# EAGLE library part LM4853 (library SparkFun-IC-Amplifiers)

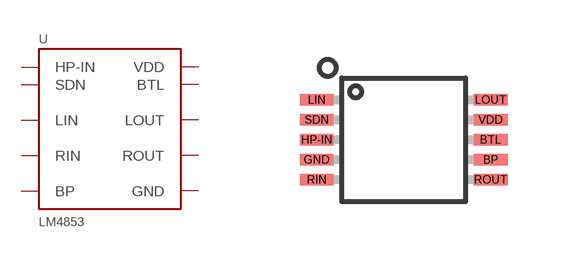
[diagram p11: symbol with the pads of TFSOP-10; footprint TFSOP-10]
Designator prefix U

## LM4853 (PROD_ID: IC-13812; VALUE: LM4853)  [TFSOP-10]
BP  BP
BTL  BTL
GND  GND
HP-IN  HP-IN
LIN  LIN
LOUT  LOUT
RIN  RIN
ROUT  ROUT
SDN  SDN
VDD  VDD

## Footprint TFSOP-10 (pad centres in mm)
smd 0.85 x 0.29: BP 2.175,-0.5; BTL 2.175,0; GND -2.175,-0.5; HP-IN -2.175,0; LIN -2.175,1; LOUT 2.175,1; RIN -2.175,-1; ROUT 2.175,-1; SDN -2.175,0.5; VDD 2.175,0.5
